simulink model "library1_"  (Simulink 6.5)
settings: Solver=ode45  StartTime=0.0  StopTime=10.0  RelTol=1e-3
libraries: HILS_model_library x16, simulink x8

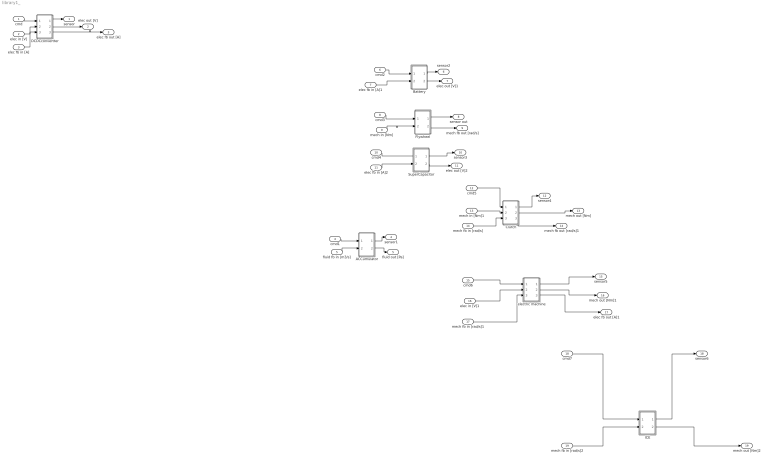
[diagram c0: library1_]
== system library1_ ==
  cmd : Inport
  elec in [V] : Inport  Port=2
  elec fb in [A] : Inport  Port=3
  cmd1 : Inport  Port=4
  fluid fb in [m3/s] : Inport  Port=5
  cmd2 : Inport  Port=6
  elec fb in [A]1 : Inport  Port=7
  cmd3 : Inport  Port=8
  mech in [Nm] : Inport  Port=9
  cmd4 : Inport  Port=10
  elec fb in [A]2 : Inport  Port=11
  cmd5 : Inport  Port=12
  mech in [Nm]1 : Inport  Port=13
  mech fb in [rad/s] : Inport  Port=14
  cmd6 : Inport  Port=15
  elec in [V]1 : Inport  Port=16
  mech fb in [rad/s]1 : Inport  Port=17
  cmd7 : Inport  Port=18
  mech fb in [rad/s]2 : Inport  Port=19
  ACCumulator : Subsystem
  Battery : Subsystem
  Clutch : Subsystem
  DCDCconvertter : Subsystem
  Flywheel : Subsystem
  ICE : Subsystem
  SuperCapacitor : Subsystem
  electric machine : Subsystem
  sensor : Outport
  elec out [V] : Outport  Port=2
  elec fb out [A] : Outport  Port=3
  sensor1 : Outport  Port=4
  fluid out [Pa] : Outport  Port=5
  sensor2 : Outport  Port=6
  elec out [V]1 : Outport  Port=7
  sensor out : Outport  Port=8
  mech fb out [rad/s] : Outport  Port=9
  sensor3 : Outport  Port=10
  elec out [V]2 : Outport  Port=11
  sensor4 : Outport  Port=12
  mech out [Nm] : Outport  Port=13
  mech fb out [rad/s]1 : Outport  Port=14
  sensor5 : Outport  Port=15
  mech out [Nm]1 : Outport  Port=16
  elec fb out [A]1 : Outport  Port=17
  sensor6 : Outport  Port=18
  mech out [Nm]2 : Outport  Port=19
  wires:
  cmd/1 -> DCDCconvertter/1(cmd)
  DCDCconvertter/1(sensor) -> sensor/1
  elec in [V]/1 -> DCDCconvertter/2(elec in [V])
  DCDCconvertter/2(elec out [V]) -> elec out [V]/1
  elec fb in [A]/1 -> DCDCconvertter/3(elec fb in [A])
  DCDCconvertter/3(elec fb out [A]) -> elec fb out [A]/1
  cmd1/1 -> ACCumulator/1(cmd1)
  ACCumulator/1(sensor1) -> sensor1/1
  fluid fb in [m3/s]/1 -> ACCumulator/2(fluid fb in [m3/s])
  ACCumulator/2(fluid out [Pa]) -> fluid out [Pa]/1
  cmd2/1 -> Battery/1(cmd2)
  Battery/1(sensor2) -> sensor2/1
  elec fb in [A]1/1 -> Battery/2(elec fb in [A]1)
  Battery/2(elec out [V]1) -> elec out [V]1/1
  cmd3/1 -> Flywheel/1(cmd3)
  Flywheel/1(sensor out) -> sensor out/1
  mech in [Nm]/1 -> Flywheel/2(mech in [Nm])
  Flywheel/2(mech fb out [rad/s]) -> mech fb out [rad/s]/1
  cmd4/1 -> SuperCapacitor/1(cmd4)
  SuperCapacitor/1(sensor3) -> sensor3/1
  elec fb in [A]2/1 -> SuperCapacitor/2(elec fb in [A]2)
  SuperCapacitor/2(elec out [V]2) -> elec out [V]2/1
  cmd5/1 -> Clutch/1(cmd5)
  Clutch/1(sensor4) -> sensor4/1
  mech in [Nm]1/1 -> Clutch/2(mech in [Nm]1)
  Clutch/2(mech out [Nm]) -> mech out [Nm]/1
  mech fb in [rad/s]/1 -> Clutch/3(mech fb in [rad/s])
  Clutch/3(mech fb out [rad/s]1) -> mech fb out [rad/s]1/1
  cmd6/1 -> electric machine/1(cmd6)
  electric machine/1(sensor5) -> sensor5/1
  elec in [V]1/1 -> electric machine/2(elec in [V]1)
  electric machine/2(mech out [Nm]1) -> mech out [Nm]1/1
  mech fb in [rad/s]1/1 -> electric machine/3(mech fb in [rad/s]1)
  electric machine/3(elec fb out [A]1) -> elec fb out [A]1/1
  cmd7/1 -> ICE/1(cmd7)
  ICE/1(sensor6) -> sensor6/1
  mech fb in [rad/s]2/1 -> ICE/2(mech fb in [rad/s]2)
  ICE/2(mech out [Nm]2) -> mech out [Nm]2/1

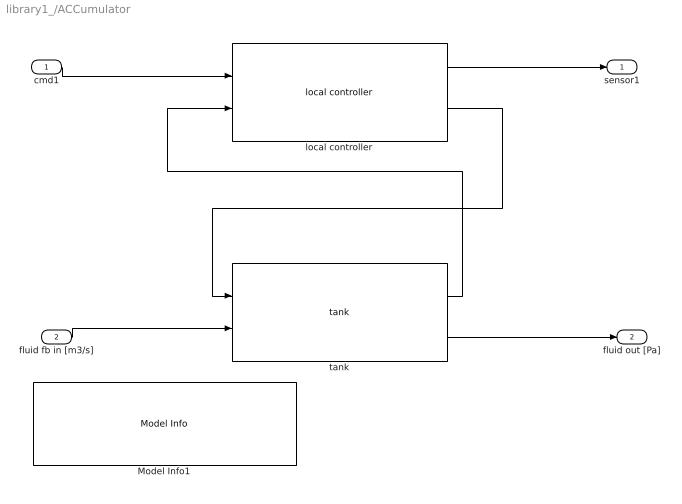
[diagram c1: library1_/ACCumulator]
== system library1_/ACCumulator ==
  cmd1 : Inport
  fluid fb in [m3/s] : Inport  Port=2
  Model Info1 : simulink/Model-Wide Utilities/Model Info  InitialBlockCM=なし  BlockCM=なし  Frame=on  DisplayStringWithTags=|  HorizontalTextAlignment=Left  LeftAlignmentValue=0.02  SourceBlockDiagram=library1_  TagMaxNumber=20
      | This model level is fixed. Place parameters in the
      | system mask on the top level. The parameter is
      | a structure specified according to GTR No XXX.
  local controller : HILS_model_library/Rechargable energy storage systems/Accumulator/local controller
  tank : HILS_model_library/Rechargable energy storage systems/Accumulator/tank
  sensor1 : Outport
  fluid out [Pa] : Outport  Port=2
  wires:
  cmd1/1 -> local controller/1
  tank/1 -> local controller/2
  fluid fb in [m3/s]/1 -> tank/2
  local controller/1 -> sensor1/1
  tank/2 -> fluid out [Pa]/1
  local controller/2 -> tank/1

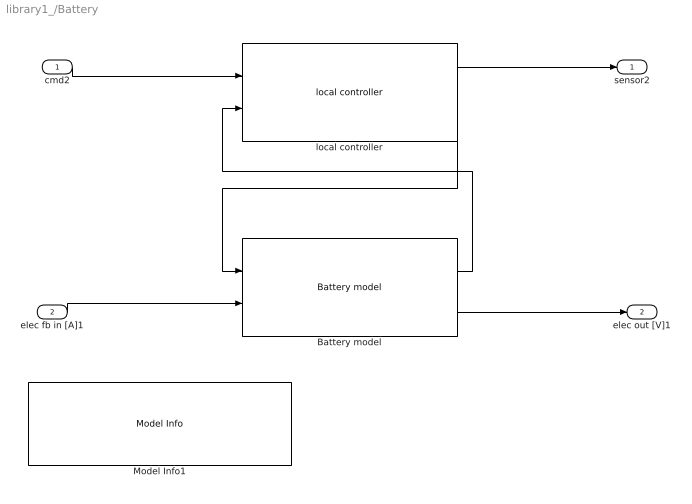
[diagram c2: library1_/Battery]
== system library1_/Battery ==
  cmd2 : Inport
  elec fb in [A]1 : Inport  Port=2
  Battery model : HILS_model_library/Rechargable energy storage systems/Battery/Battery model
  Model Info1 : simulink/Model-Wide Utilities/Model Info  InitialBlockCM=なし  BlockCM=なし  Frame=on  DisplayStringWithTags=|  HorizontalTextAlignment=Left  LeftAlignmentValue=0.02  SourceBlockDiagram=library1_  TagMaxNumber=20
      | This model level is fixed. Place parameters in the
      | system mask on the top level. The parameter is
      | a structure specified according to GTR No XXX.
  local controller : HILS_model_library/Rechargable energy storage systems/Battery/local controller
  sensor2 : Outport
  elec out [V]1 : Outport  Port=2
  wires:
  Battery model/2 -> elec out [V]1/1
  local controller/1 -> sensor2/1
  elec fb in [A]1/1 -> Battery model/2
  Battery model/1 -> local controller/2
  local controller/2 -> Battery model/1
  cmd2/1 -> local controller/1

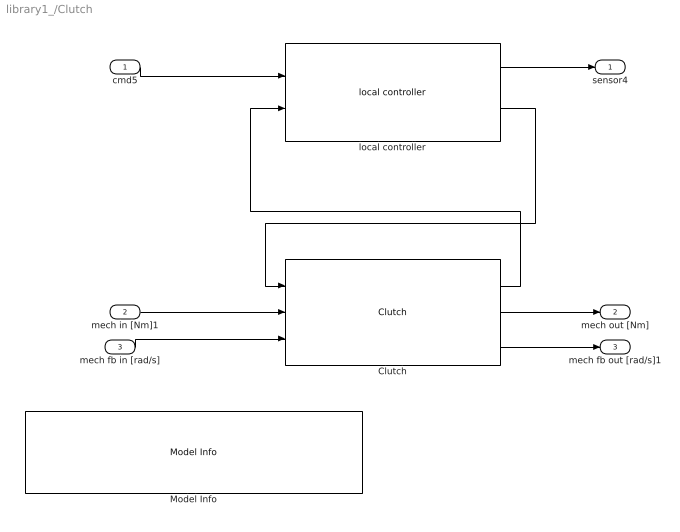
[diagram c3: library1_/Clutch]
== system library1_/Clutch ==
  cmd5 : Inport
  mech in [Nm]1 : Inport  Port=2
  mech fb in [rad/s] : Inport  Port=3
  Clutch : HILS_model_library/Mechanical components/Clutch/Clutch
  Model Info : simulink/Model-Wide Utilities/Model Info  InitialBlockCM=なし  BlockCM=なし  Frame=on  DisplayStringWithTags=|  HorizontalTextAlignment=Left  LeftAlignmentValue=0.02  SourceBlockDiagram=library1_  TagMaxNumber=20
      | This model level is fixed. Place parameters in the
      | system mask on the top level. The parameter is
      | a structure specified according to GTR No XXX.
  local controller : HILS_model_library/Mechanical components/Clutch/local controller
  sensor4 : Outport
  mech out [Nm] : Outport  Port=2
  mech fb out [rad/s]1 : Outport  Port=3
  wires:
  local controller/1 -> sensor4/1
  local controller/2 -> Clutch/1
  Clutch/1 -> local controller/2
  cmd5/1 -> local controller/1
  Clutch/3 -> mech fb out [rad/s]1/1
  mech fb in [rad/s]/1 -> Clutch/3
  Clutch/2 -> mech out [Nm]/1
  mech in [Nm]1/1 -> Clutch/2

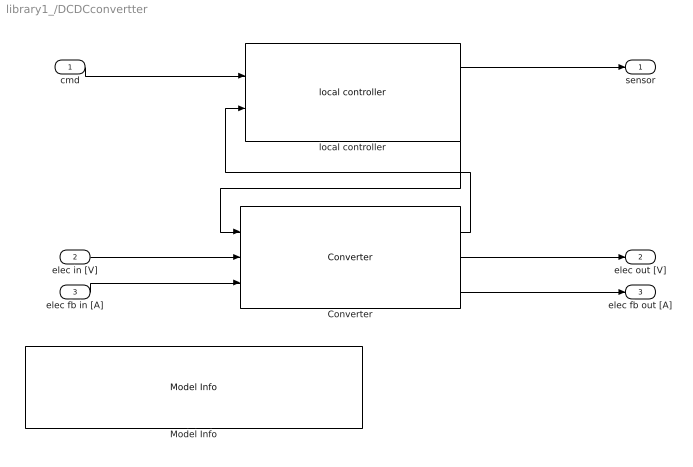
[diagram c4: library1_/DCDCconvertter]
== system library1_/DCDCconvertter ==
  cmd : Inport
  elec in [V] : Inport  Port=2
  elec fb in [A] : Inport  Port=3
  Converter : HILS_model_library/Electrical components/DCDC converter/Converter
  Model Info : simulink/Model-Wide Utilities/Model Info  InitialBlockCM=なし  BlockCM=なし  Frame=on  DisplayStringWithTags=|  HorizontalTextAlignment=Left  LeftAlignmentValue=0.02  SourceBlockDiagram=library1_  TagMaxNumber=20
      | This model level is fixed. Place parameters in the
      | system mask on the top level. The parameter is
      | a structure specified according to GTR No XXX.
  local controller : HILS_model_library/Electrical components/DCDC converter/local controller
  sensor : Outport
  elec out [V] : Outport  Port=2
  elec fb out [A] : Outport  Port=3
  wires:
  elec fb in [A]/1 -> Converter/3
  Converter/2 -> elec out [V]/1
  elec in [V]/1 -> Converter/2
  Converter/3 -> elec fb out [A]/1
  cmd/1 -> local controller/1
  local controller/2 -> Converter/1
  local controller/1 -> sensor/1
  Converter/1 -> local controller/2

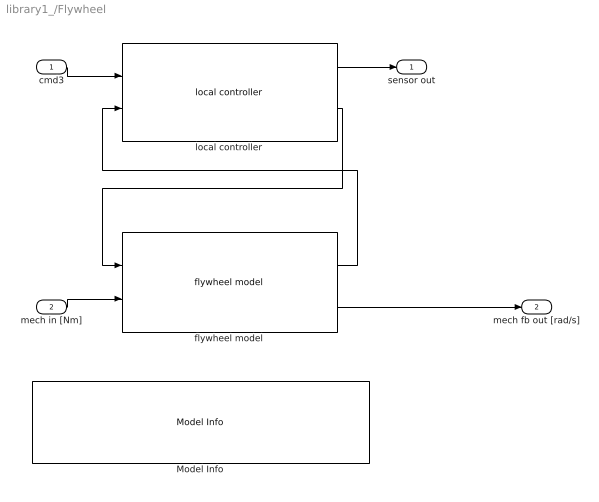
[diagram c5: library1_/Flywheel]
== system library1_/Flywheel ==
  cmd3 : Inport
  mech in [Nm] : Inport  Port=2
  Model Info : simulink/Model-Wide Utilities/Model Info  InitialBlockCM=なし  BlockCM=なし  Frame=on  DisplayStringWithTags=|  HorizontalTextAlignment=Left  LeftAlignmentValue=0.02  SourceBlockDiagram=library1_  TagMaxNumber=20
      | This model level is fixed. Place parameters in the
      | system mask on the top level. The parameter is
      | a structure specified according to GTR No XXX.
  flywheel model : HILS_model_library/Rechargable energy storage systems/Flywheel/flywheel model
  local controller : HILS_model_library/Rechargable energy storage systems/Flywheel/local controller
  sensor out : Outport
  mech fb out [rad/s] : Outport  Port=2
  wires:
  local controller/2 -> flywheel model/1
  flywheel model/1 -> local controller/2
  mech in [Nm]/1 -> flywheel model/2
  cmd3/1 -> local controller/1
  flywheel model/2 -> mech fb out [rad/s]/1
  local controller/1 -> sensor out/1

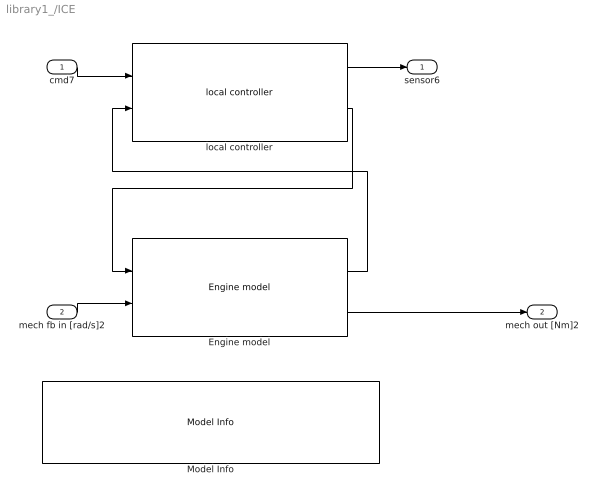
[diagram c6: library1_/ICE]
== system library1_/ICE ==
  cmd7 : Inport
  mech fb in [rad/s]2 : Inport  Port=2
  Engine model : HILS_model_library/Energy converters/Internal Combustion Engine/Engine model
  Model Info : simulink/Model-Wide Utilities/Model Info  InitialBlockCM=なし  BlockCM=なし  Frame=on  DisplayStringWithTags=|  HorizontalTextAlignment=Left  LeftAlignmentValue=0.02  SourceBlockDiagram=library1_  TagMaxNumber=20
      | This model level is fixed. Place parameters in the
      | system mask on the top level. The parameter is
      | a structure specified according to GTR No XXX.
  local controller : HILS_model_library/Energy converters/Internal Combustion Engine/local controller
  sensor6 : Outport
  mech out [Nm]2 : Outport  Port=2
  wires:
  local controller/1 -> sensor6/1
  Engine model/2 -> mech out [Nm]2/1
  cmd7/1 -> local controller/1
  mech fb in [rad/s]2/1 -> Engine model/2
  Engine model/1 -> local controller/2
  local controller/2 -> Engine model/1

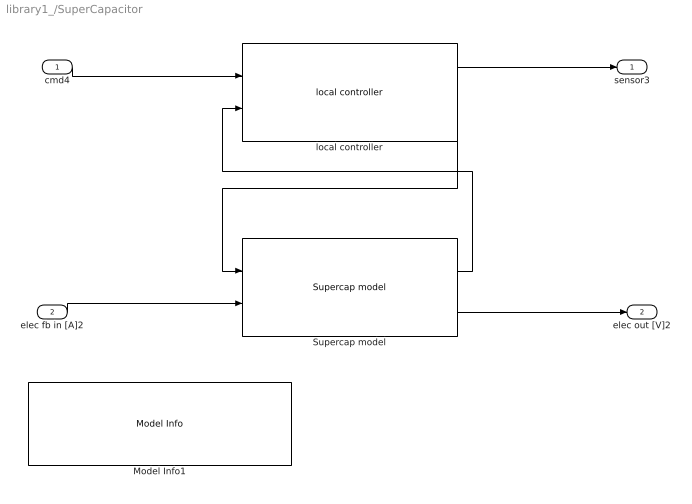
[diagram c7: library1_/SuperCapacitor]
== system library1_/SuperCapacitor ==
  cmd4 : Inport
  elec fb in [A]2 : Inport  Port=2
  Model Info1 : simulink/Model-Wide Utilities/Model Info  InitialBlockCM=なし  BlockCM=なし  Frame=on  DisplayStringWithTags=|  HorizontalTextAlignment=Left  LeftAlignmentValue=0.02  SourceBlockDiagram=library1_  TagMaxNumber=20
      | This model level is fixed. Place parameters in the
      | system mask on the top level. The parameter is
      | a structure specified according to GTR No XXX.
  Supercap model : HILS_model_library/Rechargable energy storage systems/Super Capacitor/Supercap model
  local controller : HILS_model_library/Rechargable energy storage systems/Super Capacitor/local controller
  sensor3 : Outport
  elec out [V]2 : Outport  Port=2
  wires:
  cmd4/1 -> local controller/1
  local controller/2 -> Supercap model/1
  Supercap model/1 -> local controller/2
  elec fb in [A]2/1 -> Supercap model/2
  local controller/1 -> sensor3/1
  Supercap model/2 -> elec out [V]2/1

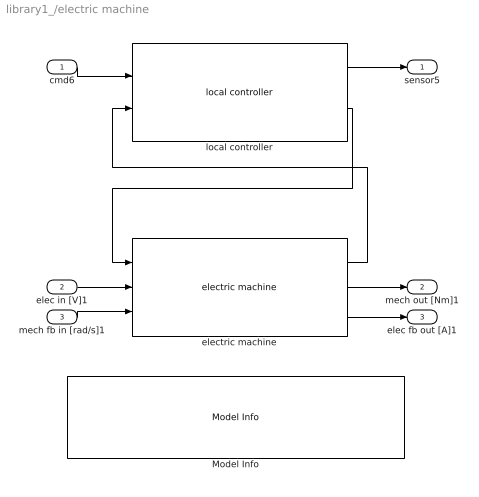
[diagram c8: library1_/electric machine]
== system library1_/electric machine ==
  cmd6 : Inport
  elec in [V]1 : Inport  Port=2
  mech fb in [rad/s]1 : Inport  Port=3
  Model Info : simulink/Model-Wide Utilities/Model Info  InitialBlockCM=なし  BlockCM=なし  Frame=on  DisplayStringWithTags=|  HorizontalTextAlignment=Left  LeftAlignmentValue=0.02  SourceBlockDiagram=library1_  TagMaxNumber=20
      | This model level is fixed. Place parameters in the
      | system mask on the top level. The parameter is
      | a structure specified according to GTR No XXX.
  electric machine : HILS_model_library/Energy converters/Electric machine/electric machine
  local controller : HILS_model_library/Energy converters/Electric machine/local controller
  sensor5 : Outport
  mech out [Nm]1 : Outport  Port=2
  elec fb out [A]1 : Outport  Port=3
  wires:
  local controller/2 -> electric machine/1
  electric machine/1 -> local controller/2
  elec in [V]1/1 -> electric machine/2
  mech fb in [rad/s]1/1 -> electric machine/3
  cmd6/1 -> local controller/1
  electric machine/3 -> elec fb out [A]1/1
  electric machine/2 -> mech out [Nm]1/1
  local controller/1 -> sensor5/1
